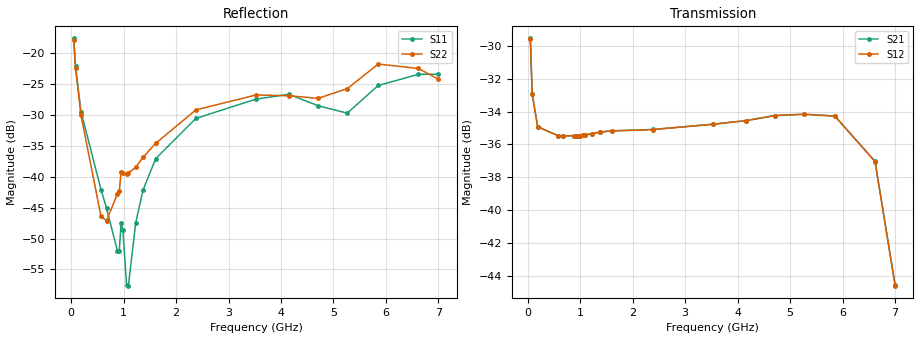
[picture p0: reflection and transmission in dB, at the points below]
! Integrated Device Technology
! Corporate Headquarters
! 6024 Silver Creek Valley Road
! San Jose, CA 95138  USA
! Phone:  1-408-284-8200
! Toll Free:  1-800-223-1366
! Webpage:  http://www.idt.com/
! Timing and RF Division
! 515 Groton Road, Suite 102
! Westford, MA 01886-6024
! Device:  F2258
! Description: Voltage Variable RF Attenuator
! Frequency:  50.0 -  6000.00 MHz
! Package:  3x3 mm Thin QFN Plastic Package: 16 pin
! Ports:  2 RF, 2 DC
!  Pin  1  = NC
!  Pin  2  = NC
!  Pin  3  = RF2  = Port 2
!  Pin  4  = GND
!  Pin  5  = Vdd
!  Pin  6  = NC
!  Pin  7  = VCTRL
!  Pin  8  = NC
!  Pin  9  = GND
!  Pin 10  = RF1  = Port 1
!  Pin 11  = NC
!  Pin 12  = NC
!  Pin 13  = NC
!  Pin 14  = NC
!  Pin 15  = NC
!  Pin 16  = NC
! Vcntrl:  2.360 Volts
! Vdd:  +3.300 Volts
! Current:  1.147 mA
! Data:  The device was measured on a the F2258 evaluation board which has
!  individual transmission lines to the RF pins.  Data was collected
!  using a calibrated network analyzer.  The evaluation board was
!  de-embedded using a TRL calibration technique.
!  The reference plane is the edge of the package pin.
! Misc:  SN 10
!  Action Tracker AT0285
! Date Measured:  2014-12-10
! Date:  2016-01-13  MJV
! Note:
!  Integrated Device Technology supplies this data as a sample of measured
!  data at the package pin for this product.  Your particular data for this
!  product may vary.
!  Data was taken at 25 degrees C.
!  Integrated Device Technology reserves the right to change this data at anytime.
!Freq_(GHz)  S11M_(dB)  S11P_(deg)  S21M_(dB)  S21P_(deg)  S12M_(dB)  S12P_(deg)  S22M_(dB)  S22P_(deg)
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# GHz S dB R 50
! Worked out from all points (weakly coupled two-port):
!   201 points, 50 MHz to 7 GHz, reference 50 ohm
!   highest |S21| = -29.53 dB at 50 MHz (marker M1); lowest = -44.6 dB at 7 GHz (marker M2)
!   lowest |S11| = -57.6 dB at 1.093 GHz (marker M3), VSWR 1.00, Z = 49.9 + j0.112 ohm
!   |S11| at or under -10 dB: start of sweep to end of sweep
!   |S22| runs from -47.1 to -17.8 dB; largest |S21 - S12| = 6.5e-05
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0.05  -17.56 -111.0  -29.53 -68.6  -29.54 -68.6  -17.79 -111.6
0.08475  -21.98 -107.4  -32.90 -48.9  -32.91 -48.9  -22.43 -108.2
0.189  -29.43 -109.4  -34.92 -24.8  -34.92 -24.8  -30.01 -111.6
0.57125  -42.07 -124.8  -35.46 -10.3  -35.46 -10.4  -46.41 -169.7
0.6755  -45.08 -131.9  -35.47 -9.4  -35.48 -9.4  -47.09 152.4
0.884  -52.00 166.5  -35.47 -8.4  -35.47 -8.4  -42.75 124.5
0.91875  -52.02 150.8  -35.47 -8.3  -35.47 -8.3  -42.35 122.2
0.9535  -47.50 -162.6  -35.48 -8.2  -35.48 -8.2  -39.17 126.3
0.98825  -48.66 -174.5  -35.46 -8.1  -35.46 -8.1  -39.45 124.4
1.05775  -57.59 154.7  -35.44 -7.9  -35.44 -7.9  -39.55 110.4
1.0925  -57.63 120.9  -35.42 -7.8  -35.42 -7.9  -39.35 106.6
1.2315  -47.48 46.3  -35.35 -7.9  -35.35 -7.8  -38.46 85.0
1.3705  -42.15 37.1  -35.25 -8.3  -35.24 -8.3  -36.84 71.3
1.61375  -37.03 32.8  -35.17 -9.5  -35.18 -9.5  -34.55 56.6
2.37825  -30.53 48.2  -35.09 -13.1  -35.10 -13.1  -29.15 45.3
3.525  -27.40 91.7  -34.77 -19.5  -34.77 -19.5  -26.73 68.7
4.1505  -26.62 105.0  -34.55 -23.9  -34.56 -23.9  -26.86 76.1
4.7065  -28.48 95.7  -34.24 -28.6  -34.24 -28.6  -27.28 59.7
5.2625  -29.67 54.3  -34.16 -34.7  -34.16 -34.7  -25.71 22.6
5.85325  -25.19 29.8  -34.27 -45.4  -34.28 -45.4  -21.72 -1.7
6.61775  -23.39 49.7  -37.03 -68.6  -37.05 -68.6  -22.44 -43.6
7  -23.37 84.5  -44.57 -61.6  -44.62 -61.0  -24.17 -130.1
